One B-rep face of a CAD part: STEP entity #25060.
In plain terms, the planar face has unit normal (0, -0.977, -0.215).
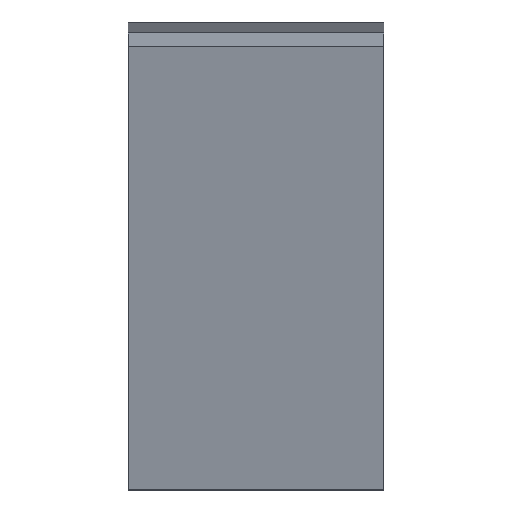
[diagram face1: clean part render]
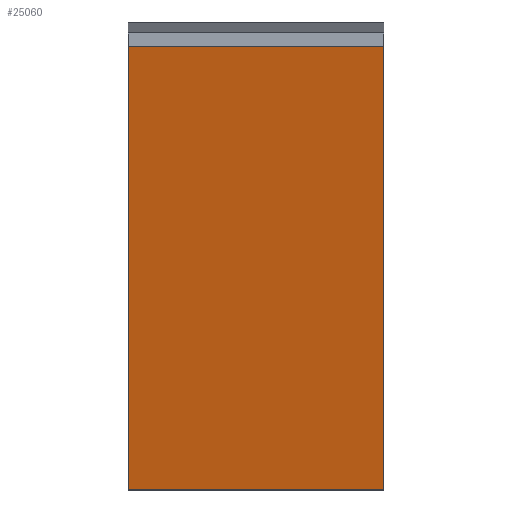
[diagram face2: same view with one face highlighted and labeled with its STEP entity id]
Its self-contained STEP definition (entity closure, numbers rounded to 3 decimals):
#72 = PLANE('',#73);
#73 = AXIS2_PLACEMENT_3D('',#74,#75,#76);
#74 = CARTESIAN_POINT('',(-28.,-12.46,-78.669));
#75 = DIRECTION('',(1.,0.,-0.));
#76 = DIRECTION('',(-0.,0.,-1.));
#126 = PLANE('',#127);
#127 = AXIS2_PLACEMENT_3D('',#128,#129,#130);
#128 = CARTESIAN_POINT('',(28.,-12.46,-78.669));
#129 = DIRECTION('',(1.,0.,-0.));
#130 = DIRECTION('',(-0.,0.,-1.));
#3959 = VERTEX_POINT('',#3960);
#3960 = CARTESIAN_POINT('',(28.,-29.338,-43.008));
#3974 = PLANE('',#3975);
#3975 = AXIS2_PLACEMENT_3D('',#3976,#3977,#3978);
#3976 = CARTESIAN_POINT('',(28.,-29.339,-43.007));
#3977 = DIRECTION('',(0.,-0.965,
    -0.262));
#3978 = DIRECTION('',(0.,0.262,-0.965)
  );
#3986 = EDGE_CURVE('',#3959,#3987,#3989,.T.);
#3987 = VERTEX_POINT('',#3988);
#3988 = CARTESIAN_POINT('',(28.,-8.,-140.));
#3989 = SURFACE_CURVE('',#3990,(#3994,#4001),.PCURVE_S1.);
#3990 = LINE('',#3991,#3992);
#3991 = CARTESIAN_POINT('',(28.,-29.338,-43.008));
#3992 = VECTOR('',#3993,1.);
#3993 = DIRECTION('',(0.,0.215,-0.977)
  );
#3994 = PCURVE('',#126,#3995);
#3995 = DEFINITIONAL_REPRESENTATION('',(#3996),#4000);
#3996 = LINE('',#3997,#3998);
#3997 = CARTESIAN_POINT('',(-35.661,-16.878));
#3998 = VECTOR('',#3999,1.);
#3999 = DIRECTION('',(0.977,0.215));
#4000 = ( GEOMETRIC_REPRESENTATION_CONTEXT(2) 
PARAMETRIC_REPRESENTATION_CONTEXT() REPRESENTATION_CONTEXT('2D SPACE',''
  ) );
#4001 = PCURVE('',#4002,#4007);
#4002 = PLANE('',#4003);
#4003 = AXIS2_PLACEMENT_3D('',#4004,#4005,#4006);
#4004 = CARTESIAN_POINT('',(28.,-29.338,-43.008));
#4005 = DIRECTION('',(0.,-0.977,
    -0.215));
#4006 = DIRECTION('',(0.,0.215,-0.977)
  );
#4007 = DEFINITIONAL_REPRESENTATION('',(#4008),#4012);
#4008 = LINE('',#4009,#4010);
#4009 = CARTESIAN_POINT('',(0.,0.));
#4010 = VECTOR('',#4011,1.);
#4011 = DIRECTION('',(1.,0.));
#4012 = ( GEOMETRIC_REPRESENTATION_CONTEXT(2) 
PARAMETRIC_REPRESENTATION_CONTEXT() REPRESENTATION_CONTEXT('2D SPACE',''
  ) );
#4030 = PLANE('',#4031);
#4031 = AXIS2_PLACEMENT_3D('',#4032,#4033,#4034);
#4032 = CARTESIAN_POINT('',(28.,-8.,-140.));
#4033 = DIRECTION('',(0.,-0.965,-0.262
    ));
#4034 = DIRECTION('',(0.,0.262,-0.965));
#16725 = VERTEX_POINT('',#16726);
#16726 = CARTESIAN_POINT('',(-28.,-29.338,-43.008));
#16747 = EDGE_CURVE('',#16725,#16748,#16750,.T.);
#16748 = VERTEX_POINT('',#16749);
#16749 = CARTESIAN_POINT('',(-28.,-8.,-140.));
#16750 = SURFACE_CURVE('',#16751,(#16755,#16762),.PCURVE_S1.);
#16751 = LINE('',#16752,#16753);
#16752 = CARTESIAN_POINT('',(-28.,-29.338,-43.008));
#16753 = VECTOR('',#16754,1.);
#16754 = DIRECTION('',(0.,0.215,-0.977
    ));
#16755 = PCURVE('',#72,#16756);
#16756 = DEFINITIONAL_REPRESENTATION('',(#16757),#16761);
#16757 = LINE('',#16758,#16759);
#16758 = CARTESIAN_POINT('',(-35.661,-16.878));
#16759 = VECTOR('',#16760,1.);
#16760 = DIRECTION('',(0.977,0.215));
#16761 = ( GEOMETRIC_REPRESENTATION_CONTEXT(2) 
PARAMETRIC_REPRESENTATION_CONTEXT() REPRESENTATION_CONTEXT('2D SPACE',''
  ) );
#16762 = PCURVE('',#4002,#16763);
#16763 = DEFINITIONAL_REPRESENTATION('',(#16764),#16768);
#16764 = LINE('',#16765,#16766);
#16765 = CARTESIAN_POINT('',(0.,-56.));
#16766 = VECTOR('',#16767,1.);
#16767 = DIRECTION('',(1.,0.));
#16768 = ( GEOMETRIC_REPRESENTATION_CONTEXT(2) 
PARAMETRIC_REPRESENTATION_CONTEXT() REPRESENTATION_CONTEXT('2D SPACE',''
  ) );
#25010 = EDGE_CURVE('',#3987,#16748,#25011,.T.);
#25011 = SURFACE_CURVE('',#25012,(#25016,#25023),.PCURVE_S1.);
#25012 = LINE('',#25013,#25014);
#25013 = CARTESIAN_POINT('',(28.,-8.,-140.));
#25014 = VECTOR('',#25015,1.);
#25015 = DIRECTION('',(-1.,0.,0.));
#25016 = PCURVE('',#4030,#25017);
#25017 = DEFINITIONAL_REPRESENTATION('',(#25018),#25022);
#25018 = LINE('',#25019,#25020);
#25019 = CARTESIAN_POINT('',(0.,0.));
#25020 = VECTOR('',#25021,1.);
#25021 = DIRECTION('',(0.,-1.));
#25022 = ( GEOMETRIC_REPRESENTATION_CONTEXT(2) 
PARAMETRIC_REPRESENTATION_CONTEXT() REPRESENTATION_CONTEXT('2D SPACE',''
  ) );
#25023 = PCURVE('',#4002,#25024);
#25024 = DEFINITIONAL_REPRESENTATION('',(#25025),#25029);
#25025 = LINE('',#25026,#25027);
#25026 = CARTESIAN_POINT('',(99.311,0.));
#25027 = VECTOR('',#25028,1.);
#25028 = DIRECTION('',(0.,-1.));
#25029 = ( GEOMETRIC_REPRESENTATION_CONTEXT(2) 
PARAMETRIC_REPRESENTATION_CONTEXT() REPRESENTATION_CONTEXT('2D SPACE',''
  ) );
#25060 = ADVANCED_FACE('',(#25061),#4002,.T.);
#25061 = FACE_BOUND('',#25062,.T.);
#25062 = EDGE_LOOP('',(#25063,#25084,#25085,#25086));
#25063 = ORIENTED_EDGE('',*,*,#25064,.T.);
#25064 = EDGE_CURVE('',#3959,#16725,#25065,.T.);
#25065 = SURFACE_CURVE('',#25066,(#25070,#25077),.PCURVE_S1.);
#25066 = LINE('',#25067,#25068);
#25067 = CARTESIAN_POINT('',(28.,-29.338,-43.008));
#25068 = VECTOR('',#25069,1.);
#25069 = DIRECTION('',(-1.,0.,0.));
#25070 = PCURVE('',#4002,#25071);
#25071 = DEFINITIONAL_REPRESENTATION('',(#25072),#25076);
#25072 = LINE('',#25073,#25074);
#25073 = CARTESIAN_POINT('',(0.,0.));
#25074 = VECTOR('',#25075,1.);
#25075 = DIRECTION('',(0.,-1.));
#25076 = ( GEOMETRIC_REPRESENTATION_CONTEXT(2) 
PARAMETRIC_REPRESENTATION_CONTEXT() REPRESENTATION_CONTEXT('2D SPACE',''
  ) );
#25077 = PCURVE('',#3974,#25078);
#25078 = DEFINITIONAL_REPRESENTATION('',(#25079),#25083);
#25079 = LINE('',#25080,#25081);
#25080 = CARTESIAN_POINT('',(0.001,0.));
#25081 = VECTOR('',#25082,1.);
#25082 = DIRECTION('',(0.,-1.));
#25083 = ( GEOMETRIC_REPRESENTATION_CONTEXT(2) 
PARAMETRIC_REPRESENTATION_CONTEXT() REPRESENTATION_CONTEXT('2D SPACE',''
  ) );
#25084 = ORIENTED_EDGE('',*,*,#16747,.T.);
#25085 = ORIENTED_EDGE('',*,*,#25010,.F.);
#25086 = ORIENTED_EDGE('',*,*,#3986,.F.);
